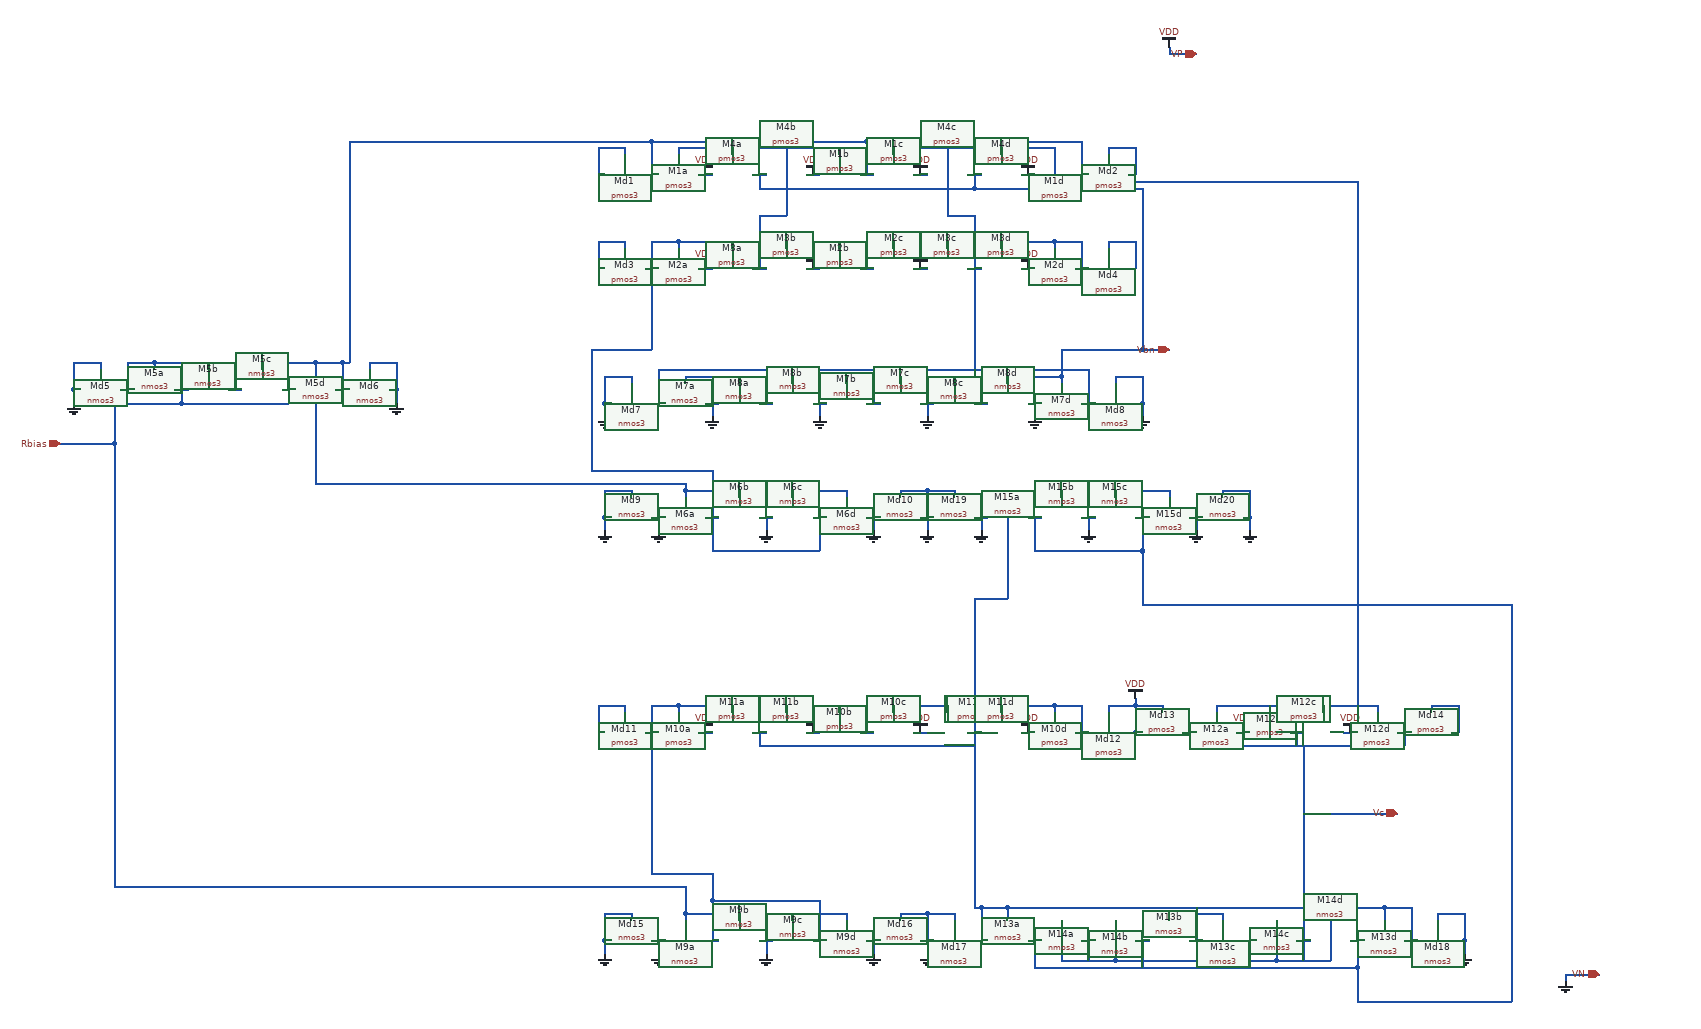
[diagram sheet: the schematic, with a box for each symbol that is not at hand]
v {xschem version=2.9.9 file_version=1.2 }
G {}
K {}
V {}
S {}
E {}
N 660 -1080 680 -1080 { lab=Rbias}
N 580 -1080 600 -1080 { lab=#net1}
N 500 -1080 520 -1080 { lab=Rbias}
N 710 -1120 710 -1110 { lab=#net1}
N 470 -1120 710 -1120 { lab=#net1}
N 470 -1120 470 -1110 { lab=#net1}
N 550 -1120 550 -1110 { lab=#net1}
N 630 -1120 630 -1110 { lab=#net1}
N 670 -1080 670 -1060 { lab=Rbias}
N 510 -1060 670 -1060 { lab=Rbias}
N 510 -1080 510 -1060 { lab=Rbias}
N 410 -1060 510 -1060 { lab=Rbias}
N 430 -1080 440 -1080 { lab=#net1}
N 740 -1080 750 -1080 { lab=#net1}
N 430 -1120 470 -1120 { lab=#net1}
N 430 -1120 430 -1080 { lab=#net1}
N 710 -1120 750 -1120 { lab=#net1}
N 750 -1120 750 -1080 { lab=#net1}
N 590 -1120 590 -1080 { lab=#net1}
N 760 -1210 760 -1120 { lab=#net1}
N 750 -1120 760 -1120 { lab=#net1}
N 750 -1080 760 -1080 { lab=#net1}
N 790 -1120 790 -1110 { lab=GND}
N 790 -1120 830 -1120 { lab=GND}
N 830 -1120 830 -1080 { lab=GND}
N 820 -1080 830 -1080 { lab=GND}
N 830 -1080 830 -1060 { lab=GND}
N 420 -1080 430 -1080 { lab=#net1}
N 390 -1120 390 -1110 { lab=GND}
N 360 -1120 390 -1120 { lab=GND}
N 350 -1080 360 -1080 { lab=GND}
N 350 -1120 360 -1120 { lab=GND}
N 350 -1120 350 -1080 { lab=GND}
N 350 -1080 350 -1060 { lab=GND}
N 410 -1060 410 -1000 { lab=Rbias}
N 330 -1000 410 -1000 { lab=Rbias}
N 1180 -1100 1180 -1090 { lab=GND}
N 1260 -1100 1260 -1090 { lab=Vbn}
N 1340 -1100 1340 -1090 { lab=Vbn}
N 1420 -1100 1420 -1090 { lab=Vbn}
N 1210 -1060 1230 -1060 { lab=#net2}
N 1290 -1060 1310 -1060 { lab=GND}
N 1370 -1060 1390 -1060 { lab=Vbn}
N 1450 -1060 1470 -1060 { lab=GND}
N 1500 -1100 1500 -1090 { lab=Vbn}
N 1580 -1100 1580 -1090 { lab=Vbn}
N 1660 -1100 1660 -1090 { lab=Vbn}
N 1740 -1100 1740 -1090 { lab=Vbn}
N 1530 -1060 1550 -1060 { lab=#net2}
N 1610 -1060 1630 -1060 { lab=GND}
N 1690 -1060 1710 -1060 { lab=Vbn}
N 1770 -1060 1790 -1060 { lab=GND}
N 1820 -1100 1820 -1090 { lab=Vbn}
N 1900 -1100 1900 -1090 { lab=GND}
N 1850 -1060 1870 -1060 { lab=#net2}
N 1260 -1100 1820 -1100 { lab=Vbn}
N 1140 -1100 1180 -1100 { lab=GND}
N 1140 -1100 1140 -1060 { lab=GND}
N 1140 -1060 1150 -1060 { lab=GND}
N 1930 -1060 1940 -1060 { lab=GND}
N 1940 -1100 1940 -1060 { lab=GND}
N 1900 -1100 1940 -1100 { lab=GND}
N 1940 -1060 1940 -1040 { lab=GND}
N 1140 -1060 1140 -1040 { lab=GND}
N 1300 -1060 1300 -1040 { lab=GND}
N 1460 -1060 1460 -1040 { lab=GND}
N 1620 -1060 1620 -1040 { lab=GND}
N 1780 -1060 1780 -1040 { lab=GND}
N 1380 -1100 1380 -1060 { lab=Vbn}
N 1700 -1100 1700 -1060 { lab=Vbn}
N 1220 -1110 1220 -1060 { lab=#net2}
N 1220 -1110 1860 -1110 { lab=#net2}
N 1860 -1110 1860 -1060 { lab=#net2}
N 1540 -1110 1540 -1060 { lab=#net2}
N 1200 -1400 1220 -1400 { lab=#net1}
N 1280 -1400 1300 -1400 { lab=VDD}
N 1360 -1400 1380 -1400 { lab=Vbn}
N 1440 -1400 1460 -1400 { lab=VDD}
N 1520 -1400 1540 -1400 { lab=#net1}
N 1600 -1400 1620 -1400 { lab=VDD}
N 1680 -1400 1700 -1400 { lab=Vbn}
N 1760 -1400 1780 -1400 { lab=VDD}
N 1840 -1400 1860 -1400 { lab=#net1}
N 1170 -1440 1170 -1430 { lab=#net3}
N 1250 -1440 1250 -1430 { lab=#net2}
N 1330 -1440 1330 -1430 { lab=#net2}
N 1410 -1440 1410 -1430 { lab=#net2}
N 1490 -1440 1490 -1430 { lab=#net2}
N 1570 -1440 1570 -1430 { lab=#net2}
N 1650 -1440 1650 -1430 { lab=#net2}
N 1730 -1440 1730 -1430 { lab=#net2}
N 1810 -1440 1810 -1430 { lab=#net2}
N 1890 -1440 1890 -1430 { lab=#net4}
N 1250 -1440 1810 -1440 { lab=#net2}
N 1890 -1440 1930 -1440 { lab=#net4}
N 1930 -1440 1930 -1400 { lab=#net4}
N 1920 -1400 1930 -1400 { lab=#net4}
N 1130 -1440 1170 -1440 { lab=#net3}
N 1130 -1440 1130 -1400 { lab=#net3}
N 1130 -1400 1140 -1400 { lab=#net3}
N 1200 -1260 1220 -1260 { lab=#net5}
N 1280 -1260 1300 -1260 { lab=VDD}
N 1360 -1260 1380 -1260 { lab=#net2}
N 1440 -1260 1460 -1260 { lab=VDD}
N 1520 -1260 1540 -1260 { lab=#net5}
N 1600 -1260 1620 -1260 { lab=VDD}
N 1680 -1260 1700 -1260 { lab=#net2}
N 1760 -1260 1780 -1260 { lab=VDD}
N 1840 -1260 1860 -1260 { lab=#net5}
N 1170 -1300 1170 -1290 { lab=#net6}
N 1250 -1300 1250 -1290 { lab=#net5}
N 1330 -1300 1330 -1290 { lab=#net5}
N 1410 -1300 1410 -1290 { lab=#net5}
N 1490 -1300 1490 -1290 { lab=#net5}
N 1570 -1300 1570 -1290 { lab=#net5}
N 1650 -1300 1650 -1290 { lab=#net5}
N 1730 -1300 1730 -1290 { lab=#net5}
N 1810 -1300 1810 -1290 { lab=#net5}
N 1890 -1300 1890 -1290 { lab=#net7}
N 1250 -1300 1810 -1300 { lab=#net5}
N 1890 -1300 1930 -1300 { lab=#net7}
N 1930 -1300 1930 -1260 { lab=#net7}
N 1920 -1260 1930 -1260 { lab=#net7}
N 1130 -1300 1170 -1300 { lab=#net6}
N 1130 -1300 1130 -1260 { lab=#net6}
N 1130 -1260 1140 -1260 { lab=#net6}
N 1530 -1450 1530 -1400 { lab=#net1}
N 1210 -1450 1530 -1450 { lab=#net1}
N 1210 -1450 1210 -1400 { lab=#net1}
N 1850 -1450 1850 -1400 { lab=#net1}
N 1530 -1450 1850 -1450 { lab=#net1}
N 1530 -1300 1530 -1260 { lab=#net5}
N 1210 -1300 1210 -1260 { lab=#net5}
N 1210 -1300 1250 -1300 { lab=#net5}
N 1850 -1300 1850 -1260 { lab=#net5}
N 1810 -1300 1850 -1300 { lab=#net5}
N 1370 -1340 1370 -1260 { lab=#net2}
N 1370 -1340 1410 -1340 { lab=#net2}
N 1410 -1430 1410 -1340 { lab=#net2}
N 1690 -1340 1690 -1260 { lab=#net2}
N 1650 -1340 1690 -1340 { lab=#net2}
N 1650 -1430 1650 -1340 { lab=#net2}
N 1370 -1400 1370 -1380 { lab=Vbn}
N 1370 -1380 1690 -1380 { lab=Vbn}
N 1690 -1400 1690 -1380 { lab=Vbn}
N 1290 -890 1310 -890 { lab=#net5}
N 1370 -890 1390 -890 { lab=GND}
N 1450 -890 1470 -890 { lab=#net5}
N 1500 -930 1500 -920 { lab=#net1}
N 1420 -930 1420 -920 { lab=#net1}
N 1340 -930 1340 -920 { lab=#net1}
N 1260 -930 1260 -920 { lab=#net1}
N 1260 -930 1500 -930 { lab=#net1}
N 1530 -890 1550 -890 { lab=GND}
N 1210 -890 1230 -890 { lab=GND}
N 1180 -930 1180 -920 { lab=GND}
N 1140 -930 1180 -930 { lab=GND}
N 1140 -930 1140 -890 { lab=GND}
N 1140 -890 1150 -890 { lab=GND}
N 1580 -930 1580 -920 { lab=GND}
N 1580 -930 1620 -930 { lab=GND}
N 1620 -930 1620 -890 { lab=GND}
N 1610 -890 1620 -890 { lab=GND}
N 1210 -1260 1210 -1220 { lab=#net5}
N 1690 -1260 1690 -1210 { lab=#net2}
N 1690 -1380 1940 -1380 { lab=Vbn}
N 1940 -1380 1940 -1210 { lab=Vbn}
N 760 -1450 1210 -1450 { lab=#net1}
N 760 -1450 760 -1210 { lab=#net1}
N 1620 -890 1620 -870 { lab=GND}
N 1540 -890 1540 -870 { lab=GND}
N 1380 -890 1380 -870 { lab=GND}
N 1220 -890 1220 -870 { lab=GND}
N 1140 -890 1140 -870 { lab=GND}
N 1460 -890 1460 -840 { lab=#net5}
N 1300 -840 1460 -840 { lab=#net5}
N 1300 -890 1300 -840 { lab=#net5}
N 1690 -1210 1690 -1110 { lab=#net2}
N 1820 -1140 1820 -1100 { lab=Vbn}
N 1820 -1140 1940 -1140 { lab=Vbn}
N 1940 -1210 1940 -1140 { lab=Vbn}
N 1210 -1220 1210 -1140 { lab=#net5}
N 1120 -1140 1210 -1140 { lab=#net5}
N 1120 -1140 1120 -960 { lab=#net5}
N 1120 -960 1300 -960 { lab=#net5}
N 1300 -960 1300 -890 { lab=#net5}
N 1260 -940 1260 -930 { lab=#net1}
N 710 -940 1260 -940 { lab=#net1}
N 710 -1110 710 -940 { lab=#net1}
N 1810 -1430 1810 -1390 { lab=#net2}
N 1810 -1390 1980 -1390 { lab=#net2}
N 1940 -1140 1980 -1140 { lab=Vbn}
N 1200 -570 1220 -570 { lab=#net8}
N 1280 -570 1300 -570 { lab=VDD}
N 1360 -570 1380 -570 { lab=#net9}
N 1440 -570 1460 -570 { lab=VDD}
N 1520 -570 1540 -570 { lab=#net8}
N 1600 -570 1620 -570 { lab=VDD}
N 1680 -570 1700 -570 { lab=#net9}
N 1760 -570 1780 -570 { lab=VDD}
N 1840 -570 1860 -570 { lab=#net8}
N 1170 -610 1170 -600 { lab=#net10}
N 1250 -610 1250 -600 { lab=#net8}
N 1330 -610 1330 -600 { lab=#net8}
N 1410 -610 1410 -600 { lab=#net8}
N 1490 -610 1490 -600 { lab=#net8}
N 1570 -610 1570 -600 { lab=#net8}
N 1650 -610 1650 -600 { lab=#net8}
N 1730 -610 1730 -600 { lab=#net8}
N 1810 -610 1810 -600 { lab=#net8}
N 1890 -610 1890 -600 { lab=VDD}
N 1250 -610 1810 -610 { lab=#net8}
N 1890 -610 1930 -610 { lab=VDD}
N 1930 -610 1930 -570 { lab=VDD}
N 1920 -570 1930 -570 { lab=VDD}
N 1130 -610 1170 -610 { lab=#net10}
N 1130 -610 1130 -570 { lab=#net10}
N 1130 -570 1140 -570 { lab=#net10}
N 1530 -610 1530 -570 { lab=#net8}
N 1210 -610 1210 -570 { lab=#net8}
N 1210 -610 1250 -610 { lab=#net8}
N 1850 -610 1850 -570 { lab=#net8}
N 1810 -610 1850 -610 { lab=#net8}
N 1210 -570 1210 -530 { lab=#net8}
N 1690 -570 1690 -520 { lab=#net9}
N 1370 -570 1370 -550 { lab=#net9}
N 1370 -550 1690 -550 { lab=#net9}
N 2000 -570 2020 -570 { lab=Vc}
N 2080 -570 2100 -570 { lab=VDD}
N 2160 -570 2180 -570 { lab=Vc}
N 2240 -570 2260 -570 { lab=VDD}
N 1970 -610 1970 -600 { lab=VDD}
N 2050 -610 2050 -600 { lab=#net2}
N 2130 -610 2130 -600 { lab=#net2}
N 2210 -610 2210 -600 { lab=#net2}
N 2290 -610 2290 -600 { lab=#net2}
N 1930 -610 1970 -610 { lab=VDD}
N 1930 -610 1930 -570 { lab=VDD}
N 1930 -570 1940 -570 { lab=VDD}
N 2170 -570 2170 -550 { lab=Vc}
N 2050 -610 2290 -610 { lab=#net2}
N 2320 -570 2340 -570 { lab=Vc}
N 2370 -610 2370 -600 { lab=#net11}
N 2370 -610 2410 -610 { lab=#net11}
N 2410 -610 2410 -570 { lab=#net11}
N 2400 -570 2410 -570 { lab=#net11}
N 1930 -620 1930 -610 { lab=VDD}
N 2330 -570 2330 -550 { lab=Vc}
N 2010 -550 2330 -550 { lab=Vc}
N 1290 -260 1310 -260 { lab=#net8}
N 1370 -260 1390 -260 { lab=GND}
N 1450 -260 1470 -260 { lab=#net8}
N 1500 -300 1500 -290 { lab=Rbias}
N 1420 -300 1420 -290 { lab=Rbias}
N 1340 -300 1340 -290 { lab=Rbias}
N 1260 -300 1260 -290 { lab=Rbias}
N 1260 -300 1500 -300 { lab=Rbias}
N 1530 -260 1550 -260 { lab=GND}
N 1210 -260 1230 -260 { lab=GND}
N 1180 -300 1180 -290 { lab=GND}
N 1140 -300 1180 -300 { lab=GND}
N 1140 -300 1140 -260 { lab=GND}
N 1140 -260 1150 -260 { lab=GND}
N 1580 -300 1580 -290 { lab=GND}
N 1580 -300 1620 -300 { lab=GND}
N 1620 -300 1620 -260 { lab=GND}
N 1610 -260 1620 -260 { lab=GND}
N 1620 -260 1620 -240 { lab=GND}
N 1540 -260 1540 -240 { lab=GND}
N 1380 -260 1380 -240 { lab=GND}
N 1220 -260 1220 -240 { lab=GND}
N 1140 -260 1140 -240 { lab=GND}
N 1260 -310 1260 -300 { lab=Rbias}
N 1260 -340 1260 -310 { lab=Rbias}
N 970 -340 1260 -340 { lab=Rbias}
N 1300 -320 1300 -260 { lab=#net8}
N 1300 -320 1460 -320 { lab=#net8}
N 1460 -320 1460 -260 { lab=#net8}
N 1300 -360 1300 -320 { lab=#net8}
N 1660 -300 1660 -290 { lab=GND}
N 1740 -300 1740 -290 { lab=#net9}
N 1690 -260 1710 -260 { lab=#net9}
N 1770 -260 1790 -260 { lab=#net12}
N 1850 -260 1870 -260 { lab=Vc}
N 1930 -260 1950 -260 { lab=#net12}
N 1980 -300 1980 -290 { lab=#net9}
N 2060 -300 2060 -290 { lab=#net9}
N 2010 -260 2030 -260 { lab=#net9}
N 2090 -260 2110 -260 { lab=#net12}
N 2170 -260 2190 -260 { lab=Vc}
N 2250 -260 2270 -260 { lab=#net12}
N 2300 -300 2300 -290 { lab=#net9}
N 2380 -300 2380 -290 { lab=GND}
N 2330 -260 2350 -260 { lab=#net9}
N 1620 -300 1660 -300 { lab=GND}
N 1620 -260 1630 -260 { lab=GND}
N 2410 -260 2420 -260 { lab=GND}
N 2420 -300 2420 -260 { lab=GND}
N 2380 -300 2420 -300 { lab=GND}
N 2420 -260 2420 -240 { lab=GND}
N 1780 -260 1780 -240 { lab=#net12}
N 1940 -260 1940 -240 { lab=#net12}
N 2100 -260 2100 -240 { lab=#net12}
N 2260 -260 2260 -240 { lab=#net12}
N 1980 -300 2060 -300 { lab=#net9}
N 1740 -310 1740 -300 { lab=#net9}
N 1740 -310 2300 -310 { lab=#net9}
N 2300 -310 2300 -300 { lab=#net9}
N 2020 -310 2020 -300 { lab=#net9}
N 2020 -300 2020 -260 { lab=#net9}
N 1700 -310 1740 -310 { lab=#net9}
N 1700 -310 1700 -260 { lab=#net9}
N 2300 -310 2340 -310 { lab=#net9}
N 2340 -310 2340 -260 { lab=#net9}
N 2010 -570 2010 -550 { lab=Vc}
N 2180 -550 2180 -260 { lab=Vc}
N 1820 -290 1820 -230 { lab=Vc}
N 1900 -290 1900 -230 { lab=Vc}
N 1820 -230 1900 -230 { lab=Vc}
N 1860 -260 1860 -230 { lab=Vc}
N 2140 -290 2140 -230 { lab=Vc}
N 2220 -290 2220 -230 { lab=Vc}
N 2140 -230 2220 -230 { lab=Vc}
N 2180 -260 2180 -230 { lab=Vc}
N 1690 -520 1690 -310 { lab=#net9}
N 1690 -310 1700 -310 { lab=#net9}
N 1210 -360 1300 -360 { lab=#net8}
N 1210 -530 1210 -360 { lab=#net8}
N 1770 -890 1790 -890 { lab=#net12}
N 1850 -890 1870 -890 { lab=GND}
N 1930 -890 1950 -890 { lab=#net12}
N 1980 -930 1980 -920 { lab=#net9}
N 1900 -930 1900 -920 { lab=#net9}
N 1820 -930 1820 -920 { lab=#net9}
N 1740 -930 1740 -920 { lab=#net9}
N 1740 -930 1980 -930 { lab=#net9}
N 2010 -890 2030 -890 { lab=GND}
N 1690 -890 1710 -890 { lab=GND}
N 1660 -930 1660 -920 { lab=GND}
N 1620 -930 1660 -930 { lab=GND}
N 1620 -890 1630 -890 { lab=GND}
N 2060 -930 2060 -920 { lab=GND}
N 2060 -930 2100 -930 { lab=GND}
N 2100 -930 2100 -890 { lab=GND}
N 2090 -890 2100 -890 { lab=GND}
N 2100 -890 2100 -870 { lab=GND}
N 2020 -890 2020 -870 { lab=GND}
N 1860 -890 1860 -870 { lab=GND}
N 1700 -890 1700 -870 { lab=GND}
N 1940 -890 1940 -840 { lab=#net12}
N 1780 -840 1940 -840 { lab=#net12}
N 1780 -890 1780 -840 { lab=#net12}
N 2260 -240 2260 -220 { lab=#net12}
N 1780 -220 2260 -220 { lab=#net12}
N 1780 -240 1780 -220 { lab=#net12}
N 1940 -240 1940 -220 { lab=#net12}
N 2100 -240 2100 -220 { lab=#net12}
N 1690 -770 1690 -570 { lab=#net9}
N 1690 -770 1740 -770 { lab=#net9}
N 1740 -920 1740 -770 { lab=#net9}
N 2260 -220 2260 -170 { lab=#net12}
N 2260 -170 2490 -170 { lab=#net12}
N 2490 -760 2490 -170 { lab=#net12}
N 1940 -760 2490 -760 { lab=#net12}
N 1940 -840 1940 -760 { lab=#net12}
N 2180 -450 2320 -450 { lab=Vc}
N 460 -340 970 -340 { lab=Rbias}
N 410 -1000 410 -340 { lab=Rbias}
N 410 -340 460 -340 { lab=Rbias}
N 1980 -1390 2260 -1390 { lab=#net2}
N 2260 -1390 2260 -610 { lab=#net2}
N 1900 -230 2140 -230 { lab=Vc}
N 2570 -210 2570 -200 { lab=GND}
N 2570 -210 2620 -210 { lab=VP}
N 1980 -1590 1980 -1580 { lab=VDD}
N 1980 -1580 2020 -1580 { lab=VP}
C {madvlsi/gnd.sym} 350 -1060 0 0 {name=l11 lab=GND}
C {madvlsi/gnd.sym} 830 -1060 0 0 {name=l12 lab=GND}
C {devices/iopin.sym} 330 -1000 2 0 {name=p1 lab=Rbias}
C {madvlsi/gnd.sym} 1140 -1040 0 0 {name=l13 lab=GND}
C {madvlsi/gnd.sym} 1940 -1040 0 0 {name=l14 lab=GND}
C {madvlsi/gnd.sym} 1300 -1040 0 0 {name=l15 lab=GND}
C {madvlsi/gnd.sym} 1460 -1040 0 0 {name=l16 lab=GND}
C {madvlsi/gnd.sym} 1620 -1040 0 0 {name=l17 lab=GND}
C {madvlsi/gnd.sym} 1780 -1040 0 0 {name=l18 lab=GND}
C {madvlsi/vdd.sym} 1610 -1400 0 0 {name=l1 lab=VDD}
C {madvlsi/vdd.sym} 1450 -1400 0 0 {name=l2 lab=VDD}
C {madvlsi/vdd.sym} 1290 -1400 0 0 {name=l3 lab=VDD}
C {madvlsi/vdd.sym} 1770 -1400 0 0 {name=l4 lab=VDD}
C {madvlsi/vdd.sym} 1450 -1260 0 0 {name=l5 lab=VDD}
C {madvlsi/vdd.sym} 1610 -1260 0 0 {name=l6 lab=VDD}
C {madvlsi/vdd.sym} 1770 -1260 0 0 {name=l7 lab=VDD}
C {madvlsi/vdd.sym} 1290 -1260 0 0 {name=l8 lab=VDD}
C {madvlsi/gnd.sym} 1140 -870 0 0 {name=l9 lab=GND}
C {madvlsi/gnd.sym} 1220 -870 0 0 {name=l10 lab=GND}
C {madvlsi/gnd.sym} 1380 -870 0 0 {name=l19 lab=GND}
C {madvlsi/gnd.sym} 1540 -870 0 0 {name=l20 lab=GND}
C {madvlsi/gnd.sym} 1620 -870 0 0 {name=l21 lab=GND}
C {devices/iopin.sym} 1980 -1140 0 0 {name=p3 lab=Vbn}
C {madvlsi/vdd.sym} 1450 -570 0 0 {name=l22 lab=VDD}
C {madvlsi/vdd.sym} 1610 -570 0 0 {name=l23 lab=VDD}
C {madvlsi/vdd.sym} 1770 -570 0 0 {name=l24 lab=VDD}
C {madvlsi/vdd.sym} 1290 -570 0 0 {name=l25 lab=VDD}
C {madvlsi/vdd.sym} 2250 -570 0 0 {name=l26 lab=VDD}
C {madvlsi/vdd.sym} 2090 -570 0 0 {name=l27 lab=VDD}
C {madvlsi/vdd.sym} 1930 -620 0 0 {name=l28 lab=VDD}
C {madvlsi/gnd.sym} 1140 -240 0 0 {name=l29 lab=GND}
C {madvlsi/gnd.sym} 1220 -240 0 0 {name=l30 lab=GND}
C {madvlsi/gnd.sym} 1380 -240 0 0 {name=l31 lab=GND}
C {madvlsi/gnd.sym} 1540 -240 0 0 {name=l32 lab=GND}
C {madvlsi/gnd.sym} 1620 -240 0 0 {name=l33 lab=GND}
C {madvlsi/gnd.sym} 2420 -240 0 0 {name=l35 lab=GND}
C {madvlsi/gnd.sym} 1700 -870 0 0 {name=l40 lab=GND}
C {madvlsi/gnd.sym} 1860 -870 0 0 {name=l41 lab=GND}
C {madvlsi/gnd.sym} 2020 -870 0 0 {name=l42 lab=GND}
C {madvlsi/gnd.sym} 2100 -870 0 0 {name=l43 lab=GND}
C {devices/iopin.sym} 2320 -450 0 0 {name=p4 lab=Vc}
C {madvlsi/nmos3.sym} 390 -1080 1 0 {name=Md5
L=0.5
W=1.4*2
body=GND
nf=1
mult=1
ad="'int((nf+1)/2) * W/nf * 0.29'" 
pd="'2*int((nf+1)/2) * (W/nf + 0.29)'"
as="'int((nf+2)/2) * W/nf * 0.29'" 
ps="'2*int((nf+2)/2) * (W/nf + 0.29)'"
nrd="'0.29 / W'" nrs="'0.29 / W'"
sa=0 sb=0 sd=0
model=nfet_01v8
spiceprefix=X
}
C {madvlsi/nmos3.sym} 470 -1080 1 0 {name=M5a
L=0.5
W=1.4*2
body=GND
nf=1
mult=1
ad="'int((nf+1)/2) * W/nf * 0.29'" 
pd="'2*int((nf+1)/2) * (W/nf + 0.29)'"
as="'int((nf+2)/2) * W/nf * 0.29'" 
ps="'2*int((nf+2)/2) * (W/nf + 0.29)'"
nrd="'0.29 / W'" nrs="'0.29 / W'"
sa=0 sb=0 sd=0
model=nfet_01v8
spiceprefix=X
}
C {madvlsi/nmos3.sym} 550 -1080 1 0 {name=M5b
L=0.5
W=1.4*2
body=GND
nf=1
mult=1
ad="'int((nf+1)/2) * W/nf * 0.29'" 
pd="'2*int((nf+1)/2) * (W/nf + 0.29)'"
as="'int((nf+2)/2) * W/nf * 0.29'" 
ps="'2*int((nf+2)/2) * (W/nf + 0.29)'"
nrd="'0.29 / W'" nrs="'0.29 / W'"
sa=0 sb=0 sd=0
model=nfet_01v8
spiceprefix=X
}
C {madvlsi/nmos3.sym} 630 -1080 1 0 {name=M5c
L=0.5
W=1.4*2
body=GND
nf=1
mult=1
ad="'int((nf+1)/2) * W/nf * 0.29'" 
pd="'2*int((nf+1)/2) * (W/nf + 0.29)'"
as="'int((nf+2)/2) * W/nf * 0.29'" 
ps="'2*int((nf+2)/2) * (W/nf + 0.29)'"
nrd="'0.29 / W'" nrs="'0.29 / W'"
sa=0 sb=0 sd=0
model=nfet_01v8
spiceprefix=X
}
C {madvlsi/nmos3.sym} 710 -1080 1 0 {name=M5d
L=0.5
W=1.4*2
body=GND
nf=1
mult=1
ad="'int((nf+1)/2) * W/nf * 0.29'" 
pd="'2*int((nf+1)/2) * (W/nf + 0.29)'"
as="'int((nf+2)/2) * W/nf * 0.29'" 
ps="'2*int((nf+2)/2) * (W/nf + 0.29)'"
nrd="'0.29 / W'" nrs="'0.29 / W'"
sa=0 sb=0 sd=0
model=nfet_01v8
spiceprefix=X
}
C {madvlsi/nmos3.sym} 790 -1080 1 0 {name=Md6
L=0.5
W=1.4*2
body=GND
nf=1
mult=1
ad="'int((nf+1)/2) * W/nf * 0.29'" 
pd="'2*int((nf+1)/2) * (W/nf + 0.29)'"
as="'int((nf+2)/2) * W/nf * 0.29'" 
ps="'2*int((nf+2)/2) * (W/nf + 0.29)'"
nrd="'0.29 / W'" nrs="'0.29 / W'"
sa=0 sb=0 sd=0
model=nfet_01v8
spiceprefix=X
}
C {madvlsi/pmos3.sym} 1170 -1400 1 0 {name=Md1
L=0.5
W=1.4/4
body=VDD
nf=1
mult=1
ad="'int((nf+1)/2) * W/nf * 0.29'" 
pd="'2*int((nf+1)/2) * (W/nf + 0.29)'"
as="'int((nf+2)/2) * W/nf * 0.29'" 
ps="'2*int((nf+2)/2) * (W/nf + 0.29)'"
nrd="'0.29 / W'" nrs="'0.29 / W'"
sa=0 sb=0 sd=0
model=pfet_01v8
spiceprefix=X
}
C {madvlsi/pmos3.sym} 1250 -1400 1 0 {name=M1a
L=0.5
W=1.4/4
body=VDD
nf=1
mult=1
ad="'int((nf+1)/2) * W/nf * 0.29'" 
pd="'2*int((nf+1)/2) * (W/nf + 0.29)'"
as="'int((nf+2)/2) * W/nf * 0.29'" 
ps="'2*int((nf+2)/2) * (W/nf + 0.29)'"
nrd="'0.29 / W'" nrs="'0.29 / W'"
sa=0 sb=0 sd=0
model=pfet_01v8
spiceprefix=X
}
C {madvlsi/pmos3.sym} 1330 -1400 1 0 {name=M4a
L=0.5
W=1.4/4
body=VDD
nf=1
mult=1
ad="'int((nf+1)/2) * W/nf * 0.29'" 
pd="'2*int((nf+1)/2) * (W/nf + 0.29)'"
as="'int((nf+2)/2) * W/nf * 0.29'" 
ps="'2*int((nf+2)/2) * (W/nf + 0.29)'"
nrd="'0.29 / W'" nrs="'0.29 / W'"
sa=0 sb=0 sd=0
model=pfet_01v8
spiceprefix=X
}
C {madvlsi/pmos3.sym} 1410 -1400 1 0 {name=M4b
L=0.5
W=1.4/4
body=VDD
nf=1
mult=1
ad="'int((nf+1)/2) * W/nf * 0.29'" 
pd="'2*int((nf+1)/2) * (W/nf + 0.29)'"
as="'int((nf+2)/2) * W/nf * 0.29'" 
ps="'2*int((nf+2)/2) * (W/nf + 0.29)'"
nrd="'0.29 / W'" nrs="'0.29 / W'"
sa=0 sb=0 sd=0
model=pfet_01v8
spiceprefix=X
}
C {madvlsi/pmos3.sym} 1490 -1400 1 0 {name=M1b
L=0.5
W=1.4/4
body=VDD
nf=1
mult=1
ad="'int((nf+1)/2) * W/nf * 0.29'" 
pd="'2*int((nf+1)/2) * (W/nf + 0.29)'"
as="'int((nf+2)/2) * W/nf * 0.29'" 
ps="'2*int((nf+2)/2) * (W/nf + 0.29)'"
nrd="'0.29 / W'" nrs="'0.29 / W'"
sa=0 sb=0 sd=0
model=pfet_01v8
spiceprefix=X
}
C {madvlsi/pmos3.sym} 1570 -1400 1 0 {name=M1c
L=0.5
W=1.4/4
body=VDD
nf=1
mult=1
ad="'int((nf+1)/2) * W/nf * 0.29'" 
pd="'2*int((nf+1)/2) * (W/nf + 0.29)'"
as="'int((nf+2)/2) * W/nf * 0.29'" 
ps="'2*int((nf+2)/2) * (W/nf + 0.29)'"
nrd="'0.29 / W'" nrs="'0.29 / W'"
sa=0 sb=0 sd=0
model=pfet_01v8
spiceprefix=X
}
C {madvlsi/pmos3.sym} 1650 -1400 1 0 {name=M4c
L=0.5
W=1.4/4
body=VDD
nf=1
mult=1
ad="'int((nf+1)/2) * W/nf * 0.29'" 
pd="'2*int((nf+1)/2) * (W/nf + 0.29)'"
as="'int((nf+2)/2) * W/nf * 0.29'" 
ps="'2*int((nf+2)/2) * (W/nf + 0.29)'"
nrd="'0.29 / W'" nrs="'0.29 / W'"
sa=0 sb=0 sd=0
model=pfet_01v8
spiceprefix=X
}
C {madvlsi/pmos3.sym} 1730 -1400 1 0 {name=M4d
L=0.5
W=1.4/4
body=VDD
nf=1
mult=1
ad="'int((nf+1)/2) * W/nf * 0.29'" 
pd="'2*int((nf+1)/2) * (W/nf + 0.29)'"
as="'int((nf+2)/2) * W/nf * 0.29'" 
ps="'2*int((nf+2)/2) * (W/nf + 0.29)'"
nrd="'0.29 / W'" nrs="'0.29 / W'"
sa=0 sb=0 sd=0
model=pfet_01v8
spiceprefix=X
}
C {madvlsi/pmos3.sym} 1810 -1400 1 0 {name=M1d
L=0.5
W=1.4/4
body=VDD
nf=1
mult=1
ad="'int((nf+1)/2) * W/nf * 0.29'" 
pd="'2*int((nf+1)/2) * (W/nf + 0.29)'"
as="'int((nf+2)/2) * W/nf * 0.29'" 
ps="'2*int((nf+2)/2) * (W/nf + 0.29)'"
nrd="'0.29 / W'" nrs="'0.29 / W'"
sa=0 sb=0 sd=0
model=pfet_01v8
spiceprefix=X
}
C {madvlsi/pmos3.sym} 1890 -1400 1 0 {name=Md2
L=0.5
W=1.4/4
body=VDD
nf=1
mult=1
ad="'int((nf+1)/2) * W/nf * 0.29'" 
pd="'2*int((nf+1)/2) * (W/nf + 0.29)'"
as="'int((nf+2)/2) * W/nf * 0.29'" 
ps="'2*int((nf+2)/2) * (W/nf + 0.29)'"
nrd="'0.29 / W'" nrs="'0.29 / W'"
sa=0 sb=0 sd=0
model=pfet_01v8
spiceprefix=X
}
C {madvlsi/pmos3.sym} 1170 -1260 1 0 {name=Md3
L=0.5
W=1.4/4
body=VDD
nf=1
mult=1
ad="'int((nf+1)/2) * W/nf * 0.29'" 
pd="'2*int((nf+1)/2) * (W/nf + 0.29)'"
as="'int((nf+2)/2) * W/nf * 0.29'" 
ps="'2*int((nf+2)/2) * (W/nf + 0.29)'"
nrd="'0.29 / W'" nrs="'0.29 / W'"
sa=0 sb=0 sd=0
model=pfet_01v8
spiceprefix=X
}
C {madvlsi/pmos3.sym} 1890 -1260 1 0 {name=Md4
L=0.5
W=1.4/4
body=VDD
nf=1
mult=1
ad="'int((nf+1)/2) * W/nf * 0.29'" 
pd="'2*int((nf+1)/2) * (W/nf + 0.29)'"
as="'int((nf+2)/2) * W/nf * 0.29'" 
ps="'2*int((nf+2)/2) * (W/nf + 0.29)'"
nrd="'0.29 / W'" nrs="'0.29 / W'"
sa=0 sb=0 sd=0
model=pfet_01v8
spiceprefix=X
}
C {madvlsi/pmos3.sym} 1250 -1260 1 0 {name=M2a
L=0.5
W=1.4/4
body=VDD
nf=1
mult=1
ad="'int((nf+1)/2) * W/nf * 0.29'" 
pd="'2*int((nf+1)/2) * (W/nf + 0.29)'"
as="'int((nf+2)/2) * W/nf * 0.29'" 
ps="'2*int((nf+2)/2) * (W/nf + 0.29)'"
nrd="'0.29 / W'" nrs="'0.29 / W'"
sa=0 sb=0 sd=0
model=pfet_01v8
spiceprefix=X
}
C {madvlsi/pmos3.sym} 1330 -1260 1 0 {name=M3a
L=0.5
W=1.4/4
body=VDD
nf=1
mult=1
ad="'int((nf+1)/2) * W/nf * 0.29'" 
pd="'2*int((nf+1)/2) * (W/nf + 0.29)'"
as="'int((nf+2)/2) * W/nf * 0.29'" 
ps="'2*int((nf+2)/2) * (W/nf + 0.29)'"
nrd="'0.29 / W'" nrs="'0.29 / W'"
sa=0 sb=0 sd=0
model=pfet_01v8
spiceprefix=X
}
C {madvlsi/pmos3.sym} 1410 -1260 1 0 {name=M3b
L=0.5
W=1.4/4
body=VDD
nf=1
mult=1
ad="'int((nf+1)/2) * W/nf * 0.29'" 
pd="'2*int((nf+1)/2) * (W/nf + 0.29)'"
as="'int((nf+2)/2) * W/nf * 0.29'" 
ps="'2*int((nf+2)/2) * (W/nf + 0.29)'"
nrd="'0.29 / W'" nrs="'0.29 / W'"
sa=0 sb=0 sd=0
model=pfet_01v8
spiceprefix=X
}
C {madvlsi/pmos3.sym} 1490 -1260 1 0 {name=M2b
L=0.5
W=1.4/4
body=VDD
nf=1
mult=1
ad="'int((nf+1)/2) * W/nf * 0.29'" 
pd="'2*int((nf+1)/2) * (W/nf + 0.29)'"
as="'int((nf+2)/2) * W/nf * 0.29'" 
ps="'2*int((nf+2)/2) * (W/nf + 0.29)'"
nrd="'0.29 / W'" nrs="'0.29 / W'"
sa=0 sb=0 sd=0
model=pfet_01v8
spiceprefix=X
}
C {madvlsi/pmos3.sym} 1570 -1260 1 0 {name=M2c
L=0.5
W=1.4/4
body=VDD
nf=1
mult=1
ad="'int((nf+1)/2) * W/nf * 0.29'" 
pd="'2*int((nf+1)/2) * (W/nf + 0.29)'"
as="'int((nf+2)/2) * W/nf * 0.29'" 
ps="'2*int((nf+2)/2) * (W/nf + 0.29)'"
nrd="'0.29 / W'" nrs="'0.29 / W'"
sa=0 sb=0 sd=0
model=pfet_01v8
spiceprefix=X
}
C {madvlsi/pmos3.sym} 1650 -1260 1 0 {name=M3c
L=0.5
W=1.4/4
body=VDD
nf=1
mult=1
ad="'int((nf+1)/2) * W/nf * 0.29'" 
pd="'2*int((nf+1)/2) * (W/nf + 0.29)'"
as="'int((nf+2)/2) * W/nf * 0.29'" 
ps="'2*int((nf+2)/2) * (W/nf + 0.29)'"
nrd="'0.29 / W'" nrs="'0.29 / W'"
sa=0 sb=0 sd=0
model=pfet_01v8
spiceprefix=X
}
C {madvlsi/pmos3.sym} 1730 -1260 1 0 {name=M3d
L=0.5
W=1.4/4
body=VDD
nf=1
mult=1
ad="'int((nf+1)/2) * W/nf * 0.29'" 
pd="'2*int((nf+1)/2) * (W/nf + 0.29)'"
as="'int((nf+2)/2) * W/nf * 0.29'" 
ps="'2*int((nf+2)/2) * (W/nf + 0.29)'"
nrd="'0.29 / W'" nrs="'0.29 / W'"
sa=0 sb=0 sd=0
model=pfet_01v8
spiceprefix=X
}
C {madvlsi/pmos3.sym} 1810 -1260 1 0 {name=M2d
L=0.5
W=1.4/4
body=VDD
nf=1
mult=1
ad="'int((nf+1)/2) * W/nf * 0.29'" 
pd="'2*int((nf+1)/2) * (W/nf + 0.29)'"
as="'int((nf+2)/2) * W/nf * 0.29'" 
ps="'2*int((nf+2)/2) * (W/nf + 0.29)'"
nrd="'0.29 / W'" nrs="'0.29 / W'"
sa=0 sb=0 sd=0
model=pfet_01v8
spiceprefix=X
}
C {madvlsi/nmos3.sym} 1180 -1060 1 0 {name=Md7
L=0.5
W=1.4/4
body=GND
nf=1
mult=1
ad="'int((nf+1)/2) * W/nf * 0.29'" 
pd="'2*int((nf+1)/2) * (W/nf + 0.29)'"
as="'int((nf+2)/2) * W/nf * 0.29'" 
ps="'2*int((nf+2)/2) * (W/nf + 0.29)'"
nrd="'0.29 / W'" nrs="'0.29 / W'"
sa=0 sb=0 sd=0
model=nfet_01v8
spiceprefix=X
}
C {madvlsi/nmos3.sym} 1900 -1060 1 0 {name=Md8
L=0.5
W=1.4/4
body=GND
nf=1
mult=1
ad="'int((nf+1)/2) * W/nf * 0.29'" 
pd="'2*int((nf+1)/2) * (W/nf + 0.29)'"
as="'int((nf+2)/2) * W/nf * 0.29'" 
ps="'2*int((nf+2)/2) * (W/nf + 0.29)'"
nrd="'0.29 / W'" nrs="'0.29 / W'"
sa=0 sb=0 sd=0
model=nfet_01v8
spiceprefix=X
}
C {madvlsi/nmos3.sym} 1260 -1060 1 0 {name=M7a
L=0.5
W=1.4/4
body=GND
nf=1
mult=1
ad="'int((nf+1)/2) * W/nf * 0.29'" 
pd="'2*int((nf+1)/2) * (W/nf + 0.29)'"
as="'int((nf+2)/2) * W/nf * 0.29'" 
ps="'2*int((nf+2)/2) * (W/nf + 0.29)'"
nrd="'0.29 / W'" nrs="'0.29 / W'"
sa=0 sb=0 sd=0
model=nfet_01v8
spiceprefix=X
}
C {madvlsi/nmos3.sym} 1340 -1060 1 0 {name=M8a
L=0.5
W=1.4/4
body=GND
nf=1
mult=1
ad="'int((nf+1)/2) * W/nf * 0.29'" 
pd="'2*int((nf+1)/2) * (W/nf + 0.29)'"
as="'int((nf+2)/2) * W/nf * 0.29'" 
ps="'2*int((nf+2)/2) * (W/nf + 0.29)'"
nrd="'0.29 / W'" nrs="'0.29 / W'"
sa=0 sb=0 sd=0
model=nfet_01v8
spiceprefix=X
}
C {madvlsi/nmos3.sym} 1420 -1060 1 0 {name=M8b
L=0.5
W=1.4/4
body=GND
nf=1
mult=1
ad="'int((nf+1)/2) * W/nf * 0.29'" 
pd="'2*int((nf+1)/2) * (W/nf + 0.29)'"
as="'int((nf+2)/2) * W/nf * 0.29'" 
ps="'2*int((nf+2)/2) * (W/nf + 0.29)'"
nrd="'0.29 / W'" nrs="'0.29 / W'"
sa=0 sb=0 sd=0
model=nfet_01v8
spiceprefix=X
}
C {madvlsi/nmos3.sym} 1500 -1060 1 0 {name=M7b
L=0.5
W=1.4/4
body=GND
nf=1
mult=1
ad="'int((nf+1)/2) * W/nf * 0.29'" 
pd="'2*int((nf+1)/2) * (W/nf + 0.29)'"
as="'int((nf+2)/2) * W/nf * 0.29'" 
ps="'2*int((nf+2)/2) * (W/nf + 0.29)'"
nrd="'0.29 / W'" nrs="'0.29 / W'"
sa=0 sb=0 sd=0
model=nfet_01v8
spiceprefix=X
}
C {madvlsi/nmos3.sym} 1580 -1060 1 0 {name=M7c
L=0.5
W=1.4/4
body=GND
nf=1
mult=1
ad="'int((nf+1)/2) * W/nf * 0.29'" 
pd="'2*int((nf+1)/2) * (W/nf + 0.29)'"
as="'int((nf+2)/2) * W/nf * 0.29'" 
ps="'2*int((nf+2)/2) * (W/nf + 0.29)'"
nrd="'0.29 / W'" nrs="'0.29 / W'"
sa=0 sb=0 sd=0
model=nfet_01v8
spiceprefix=X
}
C {madvlsi/nmos3.sym} 1660 -1060 1 0 {name=M8c
L=0.5
W=1.4/4
body=GND
nf=1
mult=1
ad="'int((nf+1)/2) * W/nf * 0.29'" 
pd="'2*int((nf+1)/2) * (W/nf + 0.29)'"
as="'int((nf+2)/2) * W/nf * 0.29'" 
ps="'2*int((nf+2)/2) * (W/nf + 0.29)'"
nrd="'0.29 / W'" nrs="'0.29 / W'"
sa=0 sb=0 sd=0
model=nfet_01v8
spiceprefix=X
}
C {madvlsi/nmos3.sym} 1740 -1060 1 0 {name=M8d
L=0.5
W=1.4/4
body=GND
nf=1
mult=1
ad="'int((nf+1)/2) * W/nf * 0.29'" 
pd="'2*int((nf+1)/2) * (W/nf + 0.29)'"
as="'int((nf+2)/2) * W/nf * 0.29'" 
ps="'2*int((nf+2)/2) * (W/nf + 0.29)'"
nrd="'0.29 / W'" nrs="'0.29 / W'"
sa=0 sb=0 sd=0
model=nfet_01v8
spiceprefix=X
}
C {madvlsi/nmos3.sym} 1820 -1060 1 0 {name=M7d
L=0.5
W=1.4/4
body=GND
nf=1
mult=1
ad="'int((nf+1)/2) * W/nf * 0.29'" 
pd="'2*int((nf+1)/2) * (W/nf + 0.29)'"
as="'int((nf+2)/2) * W/nf * 0.29'" 
ps="'2*int((nf+2)/2) * (W/nf + 0.29)'"
nrd="'0.29 / W'" nrs="'0.29 / W'"
sa=0 sb=0 sd=0
model=nfet_01v8
spiceprefix=X
}
C {madvlsi/nmos3.sym} 1180 -890 1 0 {name=Md9
L=0.5
W=1.4/4
body=GND
nf=1
mult=1
ad="'int((nf+1)/2) * W/nf * 0.29'" 
pd="'2*int((nf+1)/2) * (W/nf + 0.29)'"
as="'int((nf+2)/2) * W/nf * 0.29'" 
ps="'2*int((nf+2)/2) * (W/nf + 0.29)'"
nrd="'0.29 / W'" nrs="'0.29 / W'"
sa=0 sb=0 sd=0
model=nfet_01v8
spiceprefix=X
}
C {madvlsi/nmos3.sym} 1580 -890 1 0 {name=Md10
L=0.5
W=1.4/4
body=GND
nf=1
mult=1
ad="'int((nf+1)/2) * W/nf * 0.29'" 
pd="'2*int((nf+1)/2) * (W/nf + 0.29)'"
as="'int((nf+2)/2) * W/nf * 0.29'" 
ps="'2*int((nf+2)/2) * (W/nf + 0.29)'"
nrd="'0.29 / W'" nrs="'0.29 / W'"
sa=0 sb=0 sd=0
model=nfet_01v8
spiceprefix=X
}
C {madvlsi/nmos3.sym} 1660 -890 1 0 {name=Md19
L=0.5
W=1.4/4
body=GND
nf=1
mult=1
ad="'int((nf+1)/2) * W/nf * 0.29'" 
pd="'2*int((nf+1)/2) * (W/nf + 0.29)'"
as="'int((nf+2)/2) * W/nf * 0.29'" 
ps="'2*int((nf+2)/2) * (W/nf + 0.29)'"
nrd="'0.29 / W'" nrs="'0.29 / W'"
sa=0 sb=0 sd=0
model=nfet_01v8
spiceprefix=X
}
C {madvlsi/nmos3.sym} 2060 -890 1 0 {name=Md20
L=0.5
W=1.4/4
body=GND
nf=1
mult=1
ad="'int((nf+1)/2) * W/nf * 0.29'" 
pd="'2*int((nf+1)/2) * (W/nf + 0.29)'"
as="'int((nf+2)/2) * W/nf * 0.29'" 
ps="'2*int((nf+2)/2) * (W/nf + 0.29)'"
nrd="'0.29 / W'" nrs="'0.29 / W'"
sa=0 sb=0 sd=0
model=nfet_01v8
spiceprefix=X
}
C {madvlsi/nmos3.sym} 1260 -890 1 0 {name=M6a
L=0.5
W=1.4/4
body=GND
nf=1
mult=1
ad="'int((nf+1)/2) * W/nf * 0.29'" 
pd="'2*int((nf+1)/2) * (W/nf + 0.29)'"
as="'int((nf+2)/2) * W/nf * 0.29'" 
ps="'2*int((nf+2)/2) * (W/nf + 0.29)'"
nrd="'0.29 / W'" nrs="'0.29 / W'"
sa=0 sb=0 sd=0
model=nfet_01v8
spiceprefix=X
}
C {madvlsi/nmos3.sym} 1340 -890 1 0 {name=M6b
L=0.5
W=1.4/4
body=GND
nf=1
mult=1
ad="'int((nf+1)/2) * W/nf * 0.29'" 
pd="'2*int((nf+1)/2) * (W/nf + 0.29)'"
as="'int((nf+2)/2) * W/nf * 0.29'" 
ps="'2*int((nf+2)/2) * (W/nf + 0.29)'"
nrd="'0.29 / W'" nrs="'0.29 / W'"
sa=0 sb=0 sd=0
model=nfet_01v8
spiceprefix=X
}
C {madvlsi/nmos3.sym} 1420 -890 1 0 {name=M6c
L=0.5
W=1.4/4
body=GND
nf=1
mult=1
ad="'int((nf+1)/2) * W/nf * 0.29'" 
pd="'2*int((nf+1)/2) * (W/nf + 0.29)'"
as="'int((nf+2)/2) * W/nf * 0.29'" 
ps="'2*int((nf+2)/2) * (W/nf + 0.29)'"
nrd="'0.29 / W'" nrs="'0.29 / W'"
sa=0 sb=0 sd=0
model=nfet_01v8
spiceprefix=X
}
C {madvlsi/nmos3.sym} 1500 -890 1 0 {name=M6d
L=0.5
W=1.4/4
body=GND
nf=1
mult=1
ad="'int((nf+1)/2) * W/nf * 0.29'" 
pd="'2*int((nf+1)/2) * (W/nf + 0.29)'"
as="'int((nf+2)/2) * W/nf * 0.29'" 
ps="'2*int((nf+2)/2) * (W/nf + 0.29)'"
nrd="'0.29 / W'" nrs="'0.29 / W'"
sa=0 sb=0 sd=0
model=nfet_01v8
spiceprefix=X
}
C {madvlsi/nmos3.sym} 1740 -890 1 0 {name=M15a
L=0.5
W=1.4/4
body=GND
nf=1
mult=1
ad="'int((nf+1)/2) * W/nf * 0.29'" 
pd="'2*int((nf+1)/2) * (W/nf + 0.29)'"
as="'int((nf+2)/2) * W/nf * 0.29'" 
ps="'2*int((nf+2)/2) * (W/nf + 0.29)'"
nrd="'0.29 / W'" nrs="'0.29 / W'"
sa=0 sb=0 sd=0
model=nfet_01v8
spiceprefix=X
}
C {madvlsi/nmos3.sym} 1820 -890 1 0 {name=M15b
L=0.5
W=1.4/4
body=GND
nf=1
mult=1
ad="'int((nf+1)/2) * W/nf * 0.29'" 
pd="'2*int((nf+1)/2) * (W/nf + 0.29)'"
as="'int((nf+2)/2) * W/nf * 0.29'" 
ps="'2*int((nf+2)/2) * (W/nf + 0.29)'"
nrd="'0.29 / W'" nrs="'0.29 / W'"
sa=0 sb=0 sd=0
model=nfet_01v8
spiceprefix=X
}
C {madvlsi/nmos3.sym} 1900 -890 1 0 {name=M15c
L=0.5
W=1.4/4
body=GND
nf=1
mult=1
ad="'int((nf+1)/2) * W/nf * 0.29'" 
pd="'2*int((nf+1)/2) * (W/nf + 0.29)'"
as="'int((nf+2)/2) * W/nf * 0.29'" 
ps="'2*int((nf+2)/2) * (W/nf + 0.29)'"
nrd="'0.29 / W'" nrs="'0.29 / W'"
sa=0 sb=0 sd=0
model=nfet_01v8
spiceprefix=X
}
C {madvlsi/nmos3.sym} 1980 -890 1 0 {name=M15d
L=0.5
W=1.4/4
body=GND
nf=1
mult=1
ad="'int((nf+1)/2) * W/nf * 0.29'" 
pd="'2*int((nf+1)/2) * (W/nf + 0.29)'"
as="'int((nf+2)/2) * W/nf * 0.29'" 
ps="'2*int((nf+2)/2) * (W/nf + 0.29)'"
nrd="'0.29 / W'" nrs="'0.29 / W'"
sa=0 sb=0 sd=0
model=nfet_01v8
spiceprefix=X
}
C {madvlsi/pmos3.sym} 1170 -570 1 0 {name=Md11
L=0.5
W=1.4/4
body=VDD
nf=1
mult=1
ad="'int((nf+1)/2) * W/nf * 0.29'" 
pd="'2*int((nf+1)/2) * (W/nf + 0.29)'"
as="'int((nf+2)/2) * W/nf * 0.29'" 
ps="'2*int((nf+2)/2) * (W/nf + 0.29)'"
nrd="'0.29 / W'" nrs="'0.29 / W'"
sa=0 sb=0 sd=0
model=pfet_01v8
spiceprefix=X
}
C {madvlsi/pmos3.sym} 1890 -570 1 0 {name=Md12
L=0.5
W=1.4/4
body=VDD
nf=1
mult=1
ad="'int((nf+1)/2) * W/nf * 0.29'" 
pd="'2*int((nf+1)/2) * (W/nf + 0.29)'"
as="'int((nf+2)/2) * W/nf * 0.29'" 
ps="'2*int((nf+2)/2) * (W/nf + 0.29)'"
nrd="'0.29 / W'" nrs="'0.29 / W'"
sa=0 sb=0 sd=0
model=pfet_01v8
spiceprefix=X
}
C {madvlsi/pmos3.sym} 1970 -570 1 0 {name=Md13
L=0.5
W=1.4/4
body=VDD
nf=1
mult=1
ad="'int((nf+1)/2) * W/nf * 0.29'" 
pd="'2*int((nf+1)/2) * (W/nf + 0.29)'"
as="'int((nf+2)/2) * W/nf * 0.29'" 
ps="'2*int((nf+2)/2) * (W/nf + 0.29)'"
nrd="'0.29 / W'" nrs="'0.29 / W'"
sa=0 sb=0 sd=0
model=pfet_01v8
spiceprefix=X
}
C {madvlsi/pmos3.sym} 2370 -570 1 0 {name=Md14
L=0.5
W=1.4/4
body=VDD
nf=1
mult=1
ad="'int((nf+1)/2) * W/nf * 0.29'" 
pd="'2*int((nf+1)/2) * (W/nf + 0.29)'"
as="'int((nf+2)/2) * W/nf * 0.29'" 
ps="'2*int((nf+2)/2) * (W/nf + 0.29)'"
nrd="'0.29 / W'" nrs="'0.29 / W'"
sa=0 sb=0 sd=0
model=pfet_01v8
spiceprefix=X
}
C {madvlsi/pmos3.sym} 1250 -570 1 0 {name=M10a
L=0.5
W=1.4/4
body=VDD
nf=1
mult=1
ad="'int((nf+1)/2) * W/nf * 0.29'" 
pd="'2*int((nf+1)/2) * (W/nf + 0.29)'"
as="'int((nf+2)/2) * W/nf * 0.29'" 
ps="'2*int((nf+2)/2) * (W/nf + 0.29)'"
nrd="'0.29 / W'" nrs="'0.29 / W'"
sa=0 sb=0 sd=0
model=pfet_01v8
spiceprefix=X
}
C {madvlsi/pmos3.sym} 1330 -570 1 0 {name=M11a
L=0.5
W=1.4/4
body=VDD
nf=1
mult=1
ad="'int((nf+1)/2) * W/nf * 0.29'" 
pd="'2*int((nf+1)/2) * (W/nf + 0.29)'"
as="'int((nf+2)/2) * W/nf * 0.29'" 
ps="'2*int((nf+2)/2) * (W/nf + 0.29)'"
nrd="'0.29 / W'" nrs="'0.29 / W'"
sa=0 sb=0 sd=0
model=pfet_01v8
spiceprefix=X
}
C {madvlsi/pmos3.sym} 1410 -570 1 0 {name=M11b
L=0.5
W=1.4/4
body=VDD
nf=1
mult=1
ad="'int((nf+1)/2) * W/nf * 0.29'" 
pd="'2*int((nf+1)/2) * (W/nf + 0.29)'"
as="'int((nf+2)/2) * W/nf * 0.29'" 
ps="'2*int((nf+2)/2) * (W/nf + 0.29)'"
nrd="'0.29 / W'" nrs="'0.29 / W'"
sa=0 sb=0 sd=0
model=pfet_01v8
spiceprefix=X
}
C {madvlsi/pmos3.sym} 1490 -570 1 0 {name=M10b
L=0.5
W=1.4/4
body=VDD
nf=1
mult=1
ad="'int((nf+1)/2) * W/nf * 0.29'" 
pd="'2*int((nf+1)/2) * (W/nf + 0.29)'"
as="'int((nf+2)/2) * W/nf * 0.29'" 
ps="'2*int((nf+2)/2) * (W/nf + 0.29)'"
nrd="'0.29 / W'" nrs="'0.29 / W'"
sa=0 sb=0 sd=0
model=pfet_01v8
spiceprefix=X
}
C {madvlsi/pmos3.sym} 1570 -570 1 0 {name=M10c
L=0.5
W=1.4/4
body=VDD
nf=1
mult=1
ad="'int((nf+1)/2) * W/nf * 0.29'" 
pd="'2*int((nf+1)/2) * (W/nf + 0.29)'"
as="'int((nf+2)/2) * W/nf * 0.29'" 
ps="'2*int((nf+2)/2) * (W/nf + 0.29)'"
nrd="'0.29 / W'" nrs="'0.29 / W'"
sa=0 sb=0 sd=0
model=pfet_01v8
spiceprefix=X
}
C {madvlsi/pmos3.sym} 1650 -570 1 0 {name=M11c
L=0.5
W=1.4/4
body=VDD
nf=1
mult=1
ad="'int((nf+1)/2) * W/nf * 0.29'" 
pd="'2*int((nf+1)/2) * (W/nf + 0.29)'"
as="'int((nf+2)/2) * W/nf * 0.29'" 
ps="'2*int((nf+2)/2) * (W/nf + 0.29)'"
nrd="'0.29 / W'" nrs="'0.29 / W'"
sa=0 sb=0 sd=0
model=pfet_01v8
spiceprefix=X
}
C {madvlsi/pmos3.sym} 1730 -570 1 0 {name=M11d
L=0.5
W=1.4/4
body=VDD
nf=1
mult=1
ad="'int((nf+1)/2) * W/nf * 0.29'" 
pd="'2*int((nf+1)/2) * (W/nf + 0.29)'"
as="'int((nf+2)/2) * W/nf * 0.29'" 
ps="'2*int((nf+2)/2) * (W/nf + 0.29)'"
nrd="'0.29 / W'" nrs="'0.29 / W'"
sa=0 sb=0 sd=0
model=pfet_01v8
spiceprefix=X
}
C {madvlsi/pmos3.sym} 1810 -570 1 0 {name=M10d
L=0.5
W=1.4/4
body=VDD
nf=1
mult=1
ad="'int((nf+1)/2) * W/nf * 0.29'" 
pd="'2*int((nf+1)/2) * (W/nf + 0.29)'"
as="'int((nf+2)/2) * W/nf * 0.29'" 
ps="'2*int((nf+2)/2) * (W/nf + 0.29)'"
nrd="'0.29 / W'" nrs="'0.29 / W'"
sa=0 sb=0 sd=0
model=pfet_01v8
spiceprefix=X
}
C {madvlsi/pmos3.sym} 2050 -570 1 0 {name=M12a
L=0.5
W=1.4/4
body=VDD
nf=1
mult=1
ad="'int((nf+1)/2) * W/nf * 0.29'" 
pd="'2*int((nf+1)/2) * (W/nf + 0.29)'"
as="'int((nf+2)/2) * W/nf * 0.29'" 
ps="'2*int((nf+2)/2) * (W/nf + 0.29)'"
nrd="'0.29 / W'" nrs="'0.29 / W'"
sa=0 sb=0 sd=0
model=pfet_01v8
spiceprefix=X
}
C {madvlsi/pmos3.sym} 2130 -570 1 0 {name=M12b
L=0.5
W=1.4/4
body=VDD
nf=1
mult=1
ad="'int((nf+1)/2) * W/nf * 0.29'" 
pd="'2*int((nf+1)/2) * (W/nf + 0.29)'"
as="'int((nf+2)/2) * W/nf * 0.29'" 
ps="'2*int((nf+2)/2) * (W/nf + 0.29)'"
nrd="'0.29 / W'" nrs="'0.29 / W'"
sa=0 sb=0 sd=0
model=pfet_01v8
spiceprefix=X
}
C {madvlsi/pmos3.sym} 2210 -570 1 0 {name=M12c
L=0.5
W=1.4/4
body=VDD
nf=1
mult=1
ad="'int((nf+1)/2) * W/nf * 0.29'" 
pd="'2*int((nf+1)/2) * (W/nf + 0.29)'"
as="'int((nf+2)/2) * W/nf * 0.29'" 
ps="'2*int((nf+2)/2) * (W/nf + 0.29)'"
nrd="'0.29 / W'" nrs="'0.29 / W'"
sa=0 sb=0 sd=0
model=pfet_01v8
spiceprefix=X
}
C {madvlsi/pmos3.sym} 2290 -570 1 0 {name=M12d
L=0.5
W=1.4/4
body=VDD
nf=1
mult=1
ad="'int((nf+1)/2) * W/nf * 0.29'" 
pd="'2*int((nf+1)/2) * (W/nf + 0.29)'"
as="'int((nf+2)/2) * W/nf * 0.29'" 
ps="'2*int((nf+2)/2) * (W/nf + 0.29)'"
nrd="'0.29 / W'" nrs="'0.29 / W'"
sa=0 sb=0 sd=0
model=pfet_01v8
spiceprefix=X
}
C {madvlsi/nmos3.sym} 1180 -260 1 0 {name=Md15
L=0.5
W=1.4/4
body=GND
nf=1
mult=1
ad="'int((nf+1)/2) * W/nf * 0.29'" 
pd="'2*int((nf+1)/2) * (W/nf + 0.29)'"
as="'int((nf+2)/2) * W/nf * 0.29'" 
ps="'2*int((nf+2)/2) * (W/nf + 0.29)'"
nrd="'0.29 / W'" nrs="'0.29 / W'"
sa=0 sb=0 sd=0
model=nfet_01v8
spiceprefix=X
}
C {madvlsi/nmos3.sym} 1580 -260 1 0 {name=Md16
L=0.5
W=1.4/4
body=GND
nf=1
mult=1
ad="'int((nf+1)/2) * W/nf * 0.29'" 
pd="'2*int((nf+1)/2) * (W/nf + 0.29)'"
as="'int((nf+2)/2) * W/nf * 0.29'" 
ps="'2*int((nf+2)/2) * (W/nf + 0.29)'"
nrd="'0.29 / W'" nrs="'0.29 / W'"
sa=0 sb=0 sd=0
model=nfet_01v8
spiceprefix=X
}
C {madvlsi/nmos3.sym} 1660 -260 1 0 {name=Md17
L=0.5
W=1.4/4
body=GND
nf=1
mult=1
ad="'int((nf+1)/2) * W/nf * 0.29'" 
pd="'2*int((nf+1)/2) * (W/nf + 0.29)'"
as="'int((nf+2)/2) * W/nf * 0.29'" 
ps="'2*int((nf+2)/2) * (W/nf + 0.29)'"
nrd="'0.29 / W'" nrs="'0.29 / W'"
sa=0 sb=0 sd=0
model=nfet_01v8
spiceprefix=X
}
C {madvlsi/nmos3.sym} 2380 -260 1 0 {name=Md18
L=0.5
W=1.4/4
body=GND
nf=1
mult=1
ad="'int((nf+1)/2) * W/nf * 0.29'" 
pd="'2*int((nf+1)/2) * (W/nf + 0.29)'"
as="'int((nf+2)/2) * W/nf * 0.29'" 
ps="'2*int((nf+2)/2) * (W/nf + 0.29)'"
nrd="'0.29 / W'" nrs="'0.29 / W'"
sa=0 sb=0 sd=0
model=nfet_01v8
spiceprefix=X
}
C {madvlsi/nmos3.sym} 1260 -260 1 0 {name=M9a
L=0.5
W=1.4/4
body=GND
nf=1
mult=1
ad="'int((nf+1)/2) * W/nf * 0.29'" 
pd="'2*int((nf+1)/2) * (W/nf + 0.29)'"
as="'int((nf+2)/2) * W/nf * 0.29'" 
ps="'2*int((nf+2)/2) * (W/nf + 0.29)'"
nrd="'0.29 / W'" nrs="'0.29 / W'"
sa=0 sb=0 sd=0
model=nfet_01v8
spiceprefix=X
}
C {madvlsi/nmos3.sym} 1340 -260 1 0 {name=M9b
L=0.5
W=1.4/4
body=GND
nf=1
mult=1
ad="'int((nf+1)/2) * W/nf * 0.29'" 
pd="'2*int((nf+1)/2) * (W/nf + 0.29)'"
as="'int((nf+2)/2) * W/nf * 0.29'" 
ps="'2*int((nf+2)/2) * (W/nf + 0.29)'"
nrd="'0.29 / W'" nrs="'0.29 / W'"
sa=0 sb=0 sd=0
model=nfet_01v8
spiceprefix=X
}
C {madvlsi/nmos3.sym} 1420 -260 1 0 {name=M9c
L=0.5
W=1.4/4
body=GND
nf=1
mult=1
ad="'int((nf+1)/2) * W/nf * 0.29'" 
pd="'2*int((nf+1)/2) * (W/nf + 0.29)'"
as="'int((nf+2)/2) * W/nf * 0.29'" 
ps="'2*int((nf+2)/2) * (W/nf + 0.29)'"
nrd="'0.29 / W'" nrs="'0.29 / W'"
sa=0 sb=0 sd=0
model=nfet_01v8
spiceprefix=X
}
C {madvlsi/nmos3.sym} 1500 -260 1 0 {name=M9d
L=0.5
W=1.4/4
body=GND
nf=1
mult=1
ad="'int((nf+1)/2) * W/nf * 0.29'" 
pd="'2*int((nf+1)/2) * (W/nf + 0.29)'"
as="'int((nf+2)/2) * W/nf * 0.29'" 
ps="'2*int((nf+2)/2) * (W/nf + 0.29)'"
nrd="'0.29 / W'" nrs="'0.29 / W'"
sa=0 sb=0 sd=0
model=nfet_01v8
spiceprefix=X
}
C {madvlsi/nmos3.sym} 1740 -260 1 0 {name=M13a
L=0.5
W=1.4/4
body=GND
nf=1
mult=1
ad="'int((nf+1)/2) * W/nf * 0.29'" 
pd="'2*int((nf+1)/2) * (W/nf + 0.29)'"
as="'int((nf+2)/2) * W/nf * 0.29'" 
ps="'2*int((nf+2)/2) * (W/nf + 0.29)'"
nrd="'0.29 / W'" nrs="'0.29 / W'"
sa=0 sb=0 sd=0
model=nfet_01v8
spiceprefix=X
}
C {madvlsi/nmos3.sym} 1820 -260 1 0 {name=M14a
L=0.5
W=1.4/4
body=GND
nf=1
mult=1
ad="'int((nf+1)/2) * W/nf * 0.29'" 
pd="'2*int((nf+1)/2) * (W/nf + 0.29)'"
as="'int((nf+2)/2) * W/nf * 0.29'" 
ps="'2*int((nf+2)/2) * (W/nf + 0.29)'"
nrd="'0.29 / W'" nrs="'0.29 / W'"
sa=0 sb=0 sd=0
model=nfet_01v8
spiceprefix=X
}
C {madvlsi/nmos3.sym} 1900 -260 1 0 {name=M14b
L=0.5
W=1.4/4
body=GND
nf=1
mult=1
ad="'int((nf+1)/2) * W/nf * 0.29'" 
pd="'2*int((nf+1)/2) * (W/nf + 0.29)'"
as="'int((nf+2)/2) * W/nf * 0.29'" 
ps="'2*int((nf+2)/2) * (W/nf + 0.29)'"
nrd="'0.29 / W'" nrs="'0.29 / W'"
sa=0 sb=0 sd=0
model=nfet_01v8
spiceprefix=X
}
C {madvlsi/nmos3.sym} 1980 -260 1 0 {name=M13b
L=0.5
W=1.4/4
body=GND
nf=1
mult=1
ad="'int((nf+1)/2) * W/nf * 0.29'" 
pd="'2*int((nf+1)/2) * (W/nf + 0.29)'"
as="'int((nf+2)/2) * W/nf * 0.29'" 
ps="'2*int((nf+2)/2) * (W/nf + 0.29)'"
nrd="'0.29 / W'" nrs="'0.29 / W'"
sa=0 sb=0 sd=0
model=nfet_01v8
spiceprefix=X
}
C {madvlsi/nmos3.sym} 2060 -260 1 0 {name=M13c
L=0.5
W=1.4/4
body=GND
nf=1
mult=1
ad="'int((nf+1)/2) * W/nf * 0.29'" 
pd="'2*int((nf+1)/2) * (W/nf + 0.29)'"
as="'int((nf+2)/2) * W/nf * 0.29'" 
ps="'2*int((nf+2)/2) * (W/nf + 0.29)'"
nrd="'0.29 / W'" nrs="'0.29 / W'"
sa=0 sb=0 sd=0
model=nfet_01v8
spiceprefix=X
}
C {madvlsi/nmos3.sym} 2140 -260 1 0 {name=M14c
L=0.5
W=1.4/4
body=GND
nf=1
mult=1
ad="'int((nf+1)/2) * W/nf * 0.29'" 
pd="'2*int((nf+1)/2) * (W/nf + 0.29)'"
as="'int((nf+2)/2) * W/nf * 0.29'" 
ps="'2*int((nf+2)/2) * (W/nf + 0.29)'"
nrd="'0.29 / W'" nrs="'0.29 / W'"
sa=0 sb=0 sd=0
model=nfet_01v8
spiceprefix=X
}
C {madvlsi/nmos3.sym} 2220 -260 1 0 {name=M14d
L=0.5
W=1.4/4
body=GND
nf=1
mult=1
ad="'int((nf+1)/2) * W/nf * 0.29'" 
pd="'2*int((nf+1)/2) * (W/nf + 0.29)'"
as="'int((nf+2)/2) * W/nf * 0.29'" 
ps="'2*int((nf+2)/2) * (W/nf + 0.29)'"
nrd="'0.29 / W'" nrs="'0.29 / W'"
sa=0 sb=0 sd=0
model=nfet_01v8
spiceprefix=X
}
C {madvlsi/nmos3.sym} 2300 -260 1 0 {name=M13d
L=0.5
W=1.4/4
body=GND
nf=1
mult=1
ad="'int((nf+1)/2) * W/nf * 0.29'" 
pd="'2*int((nf+1)/2) * (W/nf + 0.29)'"
as="'int((nf+2)/2) * W/nf * 0.29'" 
ps="'2*int((nf+2)/2) * (W/nf + 0.29)'"
nrd="'0.29 / W'" nrs="'0.29 / W'"
sa=0 sb=0 sd=0
model=nfet_01v8
spiceprefix=X
}
C {madvlsi/gnd.sym} 2570 -200 0 0 {name=l34 lab=GND}
C {madvlsi/vdd.sym} 1980 -1590 0 0 {name=l36 lab=VDD}
C {devices/iopin.sym} 2020 -1580 0 0 {name=p2 lab=VP}
C {devices/iopin.sym} 2620 -210 0 0 {name=p5 lab=VN}
